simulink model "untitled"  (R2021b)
settings: Solver=FixedStepDiscrete  StartTime=0.0  StopTime=inf  FixedStep=0.01  RelTol=1e-3
undefined symbols (not defined in the file): RS485
libraries: PWM_Control_lib x6, PWM_SetDuty_lib x6, RS485_1_TxBytes_lib x1, Sensor_ReadData_lib x1, PWM_Init_lib x1, Sensor_Add_lib x1, sculib x1, Now_lib x1

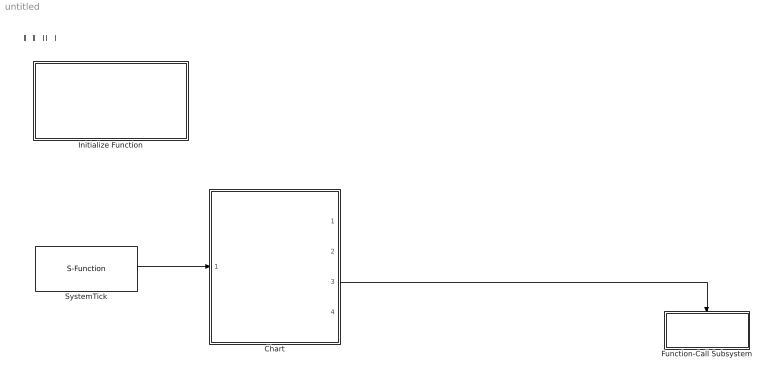
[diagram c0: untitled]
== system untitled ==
  note: 整个系统的初始化
  Chart : Stateflow chart  TreatAsAtomicUnit=on
  Function-Call Subsystem : Subsystem  TreatAsAtomicUnit=on
  Initialize Function : Subsystem  TreatAsAtomicUnit=on
  SystemTick : Now_lib/S-Function  SFunctionModules=''
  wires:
  SystemTick/1 -> Chart/1(systick)
  Chart/3(call_1S()) -> Function-Call Subsystem/Trigger

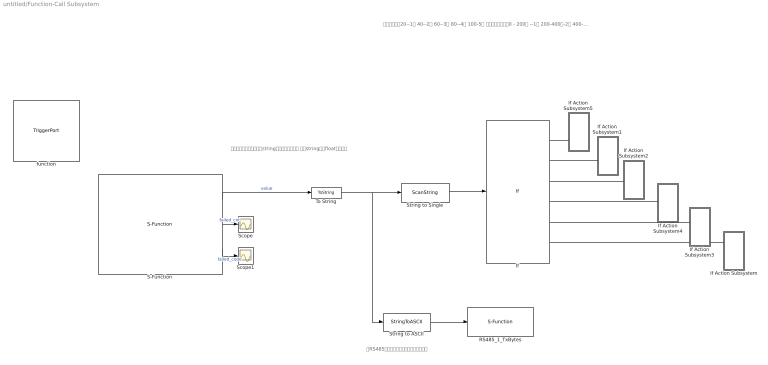
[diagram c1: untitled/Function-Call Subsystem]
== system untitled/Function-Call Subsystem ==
  note: 在RS485监控数据，方便监测是否读取成功
  note: 将输出的信号类型转换成string（字符串）类型， 再将string转换float（浮点）
  note: 占空比调节：20--1挡 40--2挡 60--3挡 80--4挡 100-5挡 多重判断：当值在0 - 200时 --1挡 200-400时-2挡 400-600时-3挡 600-800时-4挡 大于800时-5挡
  function : TriggerPort  TriggerType=function-call  VariantControl=(inherit)
  If : If  IfExpression=u1<0 & u1==-9999  ElseIfExpressions=u1>=0&u1<200,u1>=200&u1<400,u1>=400&u1<600,u1>=600&u1<800
  If Action Subsystem : Subsystem  TreatAsAtomicUnit=on
  If Action Subsystem1 : Subsystem  TreatAsAtomicUnit=on
  If Action Subsystem2 : Subsystem  TreatAsAtomicUnit=on
  If Action Subsystem3 : Subsystem  TreatAsAtomicUnit=on
  If Action Subsystem4 : Subsystem  TreatAsAtomicUnit=on
  If Action Subsystem5 : Subsystem  TreatAsAtomicUnit=on
  RS485_1_TxBytes : RS485_1_TxBytes_lib/S-Function  vu8=0
  S-Function : Sensor_ReadData_lib/S-Function  Priority=0  interface=RS485-2  index=0
  Scope : Scope
  Scope1 : Scope
  String to ASCII : StringToASCII  OutputVectorSize=6
  String to Single : ScanString  Priority=2  Format="\"%f\""
  To String : ToString  Priority=1
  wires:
  S-Function/2 -> Scope/1  "failed_cnt"
  S-Function/3 -> Scope1/1  "failed_code"
  S-Function/1 -> To String/1  "value"
  To String/1 -> String to ASCII/1, String to Single/1
  String to Single/1 -> If/1
  If/1 -> If Action Subsystem5/Action
  If/2 -> If Action Subsystem1/Action
  If/3 -> If Action Subsystem2/Action
  If/4 -> If Action Subsystem4/Action
  If/5 -> If Action Subsystem3/Action
  If/6 -> If Action Subsystem/Action
  String to ASCII/1 -> RS485_1_TxBytes/1

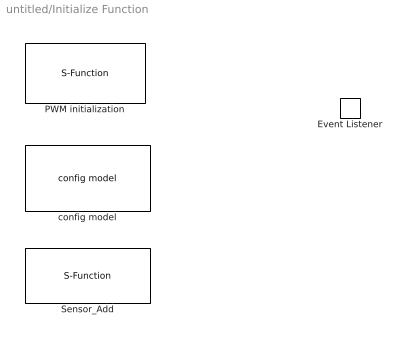
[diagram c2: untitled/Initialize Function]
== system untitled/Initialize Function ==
  Event Listener : EventListener  DisableCoverage=on  EventName=reset
  PWM initialization : PWM_Init_lib/S-Function
  Sensor_Add : Sensor_Add_lib/S-Function  interface=RS485-2  index=0  model=User Customize  data_type=Unsigned  msb=MSB  ratio=1.0  invalid_value=-9999  addr=1  start=2  len=2
  config model : sculib/SCU001/config model  Priority=0  iap=Uart2  uart1_baudrate=9600  uart2_baudrate=115200  rs485_1_baudrate=4800  rs485_2_baudrate=4800  rs485_1_read_interval=10  rs485_2_read_interval=10

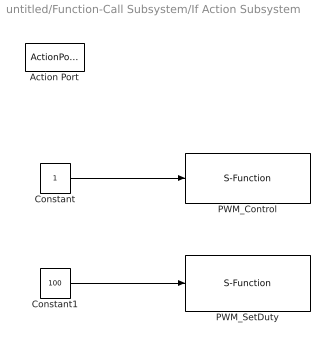
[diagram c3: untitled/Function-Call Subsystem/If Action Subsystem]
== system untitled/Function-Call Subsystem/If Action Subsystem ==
  Action Port : ActionPort  ActionPortLabel=else
  Constant : Constant  OutDataTypeStr=uint8
  Constant1 : Constant  Value=100  OutDataTypeStr=uint16
  PWM_Control : PWM_Control_lib/S-Function  vu8=0
  PWM_SetDuty : PWM_SetDuty_lib/S-Function  vu16=0
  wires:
  Constant1/1 -> PWM_SetDuty/1
  Constant/1 -> PWM_Control/1

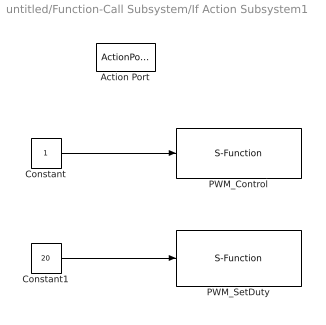
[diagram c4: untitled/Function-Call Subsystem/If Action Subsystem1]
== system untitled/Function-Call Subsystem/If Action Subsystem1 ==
  Action Port : ActionPort  ActionPortLabel=elseif(u1>=0&u1<200)
  Constant : Constant  OutDataTypeStr=uint8
  Constant1 : Constant  Value=20  OutDataTypeStr=uint16
  PWM_Control : PWM_Control_lib/S-Function  vu8=0
  PWM_SetDuty : PWM_SetDuty_lib/S-Function  vu16=0
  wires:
  Constant1/1 -> PWM_SetDuty/1
  Constant/1 -> PWM_Control/1

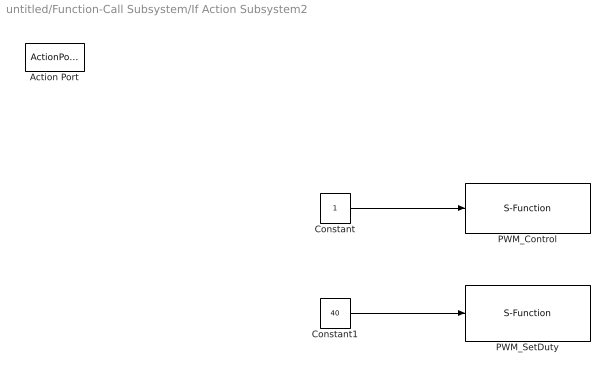
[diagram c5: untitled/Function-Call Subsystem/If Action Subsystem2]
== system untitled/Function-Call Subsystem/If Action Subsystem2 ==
  Action Port : ActionPort  ActionPortLabel=elseif(u1>=200&u1<400)
  Constant : Constant  OutDataTypeStr=uint8
  Constant1 : Constant  Value=40  OutDataTypeStr=uint16
  PWM_Control : PWM_Control_lib/S-Function  vu8=0
  PWM_SetDuty : PWM_SetDuty_lib/S-Function  vu16=0
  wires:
  Constant1/1 -> PWM_SetDuty/1
  Constant/1 -> PWM_Control/1

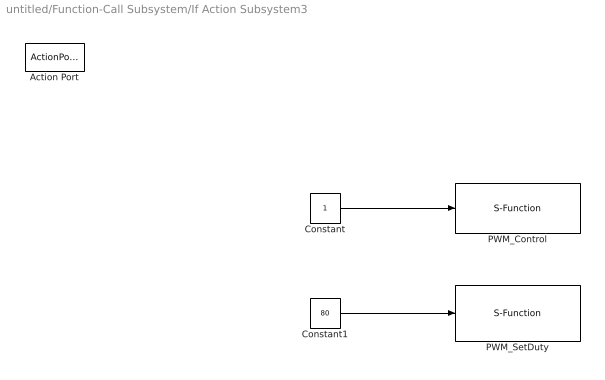
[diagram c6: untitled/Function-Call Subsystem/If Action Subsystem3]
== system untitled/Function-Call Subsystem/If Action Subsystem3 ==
  Action Port : ActionPort  ActionPortLabel=elseif(u1>=600&u1<800)
  Constant : Constant  OutDataTypeStr=uint8
  Constant1 : Constant  Value=80  OutDataTypeStr=uint16
  PWM_Control : PWM_Control_lib/S-Function  vu8=0
  PWM_SetDuty : PWM_SetDuty_lib/S-Function  vu16=0
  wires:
  Constant1/1 -> PWM_SetDuty/1
  Constant/1 -> PWM_Control/1

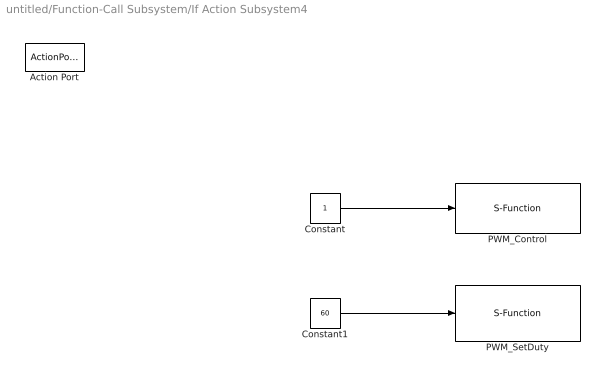
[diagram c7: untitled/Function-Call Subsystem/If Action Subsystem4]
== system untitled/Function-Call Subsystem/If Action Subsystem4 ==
  Action Port : ActionPort  ActionPortLabel=elseif(u1>=400&u1<600)
  Constant : Constant  OutDataTypeStr=uint8
  Constant1 : Constant  Value=60  OutDataTypeStr=uint16
  PWM_Control : PWM_Control_lib/S-Function  vu8=0
  PWM_SetDuty : PWM_SetDuty_lib/S-Function  vu16=0
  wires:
  Constant1/1 -> PWM_SetDuty/1
  Constant/1 -> PWM_Control/1

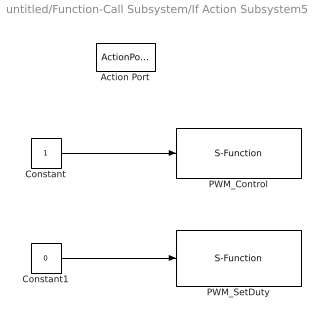
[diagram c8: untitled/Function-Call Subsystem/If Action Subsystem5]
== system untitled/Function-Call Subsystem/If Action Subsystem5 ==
  Action Port : ActionPort  ActionPortLabel=if(u1<0 & u1==-9999)
  Constant : Constant  OutDataTypeStr=uint8
  Constant1 : Constant  Value=0  OutDataTypeStr=uint16
  PWM_Control : PWM_Control_lib/S-Function  vu8=0
  PWM_SetDuty : PWM_SetDuty_lib/S-Function  vu16=0
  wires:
  Constant1/1 -> PWM_SetDuty/1
  Constant/1 -> PWM_Control/1

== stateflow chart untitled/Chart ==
  (default) -> (junction 1)
  (junction 1) -> (junction 31) : {call_10MS}
  (junction 31) -> (junction 35) : [rem(systick,10)==0]
  (junction 35) -> (junction 37) : {call_100MS}
  (junction 31) -> (junction 37)
  (junction 37) -> (junction 42) : [rem(systick,100)==0]
  (junction 42) -> (junction 44) : {call_1S}
  (junction 37) -> (junction 44)
  (junction 44) -> (junction 51) : [rem(systick,1000)==0]
  (junction 51) -> (junction 53) : {call_10S;}
  (junction 44) -> (junction 53)
  data: systick input
  events: output FUNCTION_CALL_EVENT; output FUNCTION_CALL_EVENT; output FUNCTION_CALL_EVENT; output FUNCTION_CALL_EVENT
